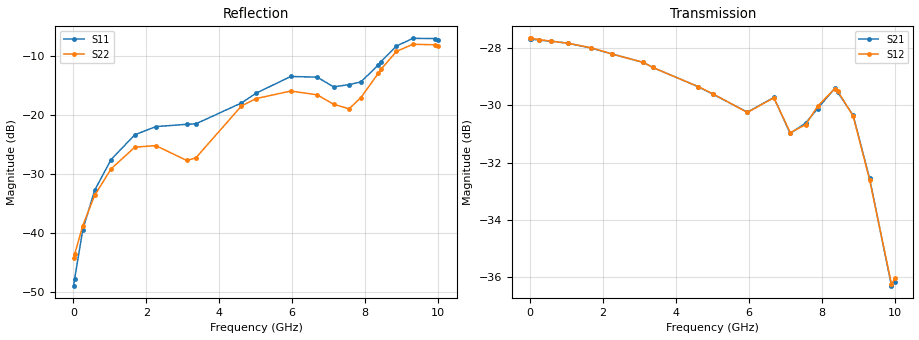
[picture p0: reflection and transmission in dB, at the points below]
! Device ID: PE43704
! Dir: z:\PE43704\PE43704_Char_1_20130516\PE43704\AMB\3p400V\26p75dB
! Serial: 14
! Insertion: A
! Impedance: 50 ohm
! Temp: Amb
! VDD: 3.400V
! Attenuation Step: 26.75dB
! IDD: 1.139951e-01mA
#  Hz  S  RI  R  50
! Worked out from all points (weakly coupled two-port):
!   401 points, 10 MHz to 10.01 GHz, reference 50 ohm
!   highest |S21| = -27.67 dB at 35 MHz (marker M1); lowest = -36.3 dB at 9.91 GHz (marker M2)
!   lowest |S11| = -49.0 dB at 10 MHz (marker M3), VSWR 1.01, Z = 50.4 + j0.0386 ohm
!   |S11| at or under -10 dB: start of sweep to 8.562 GHz
!   |S22| runs from -44.3 to -7.8 dB; largest |S21 - S12| = 0.00064
!   S11 on the Smith chart (normalised r, x): 10 MHz: 1.01, +0.00; 4.61 GHz: 0.79, +0.08; 8.435 GHz: 0.76, +0.46; 9.31 GHz: 0.51, +0.52; 10.01 GHz: 0.44, +0.31
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1e7  0.00353 0.000384  0.0413 -0.000146  0.0414 -0.000111  0.00608 0.000399
3.5e7  0.00374 0.0015  0.0413 -0.000373  0.0414 -0.000423  0.00636 0.00153
2.6e8  0.0011 0.0106  0.041 -0.00276  0.0411 -0.00271  0.00425 0.0107
5.85e8  -0.0097 0.0208  0.0405 -0.00598  0.0405 -0.00595  -0.00563 0.02
1.035e9  -0.0346 0.0236  0.0393 -0.0102  0.0393 -0.0102  -0.0277 0.0213
1.685e9  -0.0677 0.00652  0.0365 -0.0159  0.0365 -0.016  -0.0533 0.0025
2.26e9  -0.0789 -0.0122  0.0332 -0.0202  0.0332 -0.0202  -0.0536 -0.0126
3.11e9  -0.0818 -0.017  0.0276 -0.0255  0.0277 -0.0254  -0.041 -0.00363
3.36e9  -0.0836 -0.0108  0.0257 -0.0264  0.0257 -0.0264  -0.043 0.00537
4.61e9  -0.1166 0.0499  0.0171 -0.0295  0.0171 -0.0295  -0.1048 0.0577
5.01e9  -0.136 0.0711  0.015 -0.0295  0.0151 -0.0295  -0.1257 0.0572
5.96e9  -0.1865 0.1027  0.00906 -0.0294  0.00926 -0.0293  -0.1506 0.0544
6.685e9  -0.187 0.0962  0.00643 -0.032  0.00623 -0.032  -0.1391 0.0529
7.135e9  -0.1545 0.0795  0.00148 -0.0282  0.00157 -0.0283  -0.1039 0.0671
7.56e9  -0.1299 0.1269  0.00196 -0.0294  0.00186 -0.0292  -0.0682 0.0902
7.885e9  -0.0904 0.1688  0.000809 -0.0312  0.001 -0.0315  -0.0576 0.1286
8.36e9  -0.0595 0.2596  -0.00676 -0.0332  -0.00702 -0.0331  -0.0732 0.2143
8.435e9  -0.0605 0.2787  -0.00822 -0.0323  -0.00821 -0.0325  -0.0817 0.2308
8.86e9  -0.1004 0.3731  -0.0145 -0.0267  -0.0143 -0.0267  -0.1384 0.3192
9.31e9  -0.1828 0.41  -0.0141 -0.0189  -0.0139 -0.0189  -0.2229 0.3322
9.91e9  -0.3113 0.3215  -0.00491 -0.0145  -0.00522 -0.0145  -0.3413 0.2002
1.001e10  -0.3286 0.2887  -0.00333 -0.0152  -0.00335 -0.0154  -0.3534 0.1629
